VERSION 5.8 ;
BUSBITCHARS "[]" ;
DIVIDERCHAR "/" ;
UNITS
    DATABASE MICRONS 1000 ;
END UNITS

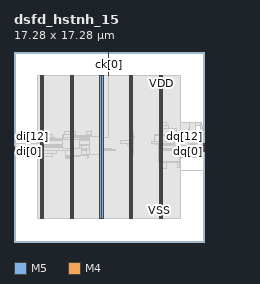
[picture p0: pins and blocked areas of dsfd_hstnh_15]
MACRO dsfd_hstnh_15
  FOREIGN dsfd_hstnh_15 0 0 ;
  CLASS BLOCK ;
  SIZE 17.28 BY 17.28 ;
  PIN ck[0]
    DIRECTION INPUT ;
    USE SIGNAL ;
    PORT
      LAYER M5 ;
        RECT  8.592 17.196 8.616 17.28 ;
    END
    PORT
      LAYER M5 ;
        RECT  8.592 15.143 8.616 17.232 ;
    END
  END ck[0]
  PIN di[0]
    DIRECTION INPUT ;
    USE SIGNAL ;
    PORT
      LAYER M4 ;
        RECT  0 8.256 0.084 8.28 ;
    END
  END di[0]
  PIN di[10]
    DIRECTION INPUT ;
    USE SIGNAL ;
    PORT
      LAYER M4 ;
        RECT  0 8.736 0.084 8.76 ;
    END
  END di[10]
  PIN di[11]
    DIRECTION INPUT ;
    USE SIGNAL ;
    PORT
      LAYER M4 ;
        RECT  0 8.784 0.084 8.808 ;
    END
  END di[11]
  PIN di[12]
    DIRECTION INPUT ;
    USE SIGNAL ;
    PORT
      LAYER M4 ;
        RECT  0 8.832 0.084 8.856 ;
    END
  END di[12]
  PIN di[13]
    DIRECTION INPUT ;
    USE SIGNAL ;
    PORT
      LAYER M4 ;
        RECT  0 8.88 0.084 8.904 ;
    END
  END di[13]
  PIN di[14]
    DIRECTION INPUT ;
    USE SIGNAL ;
    PORT
      LAYER M4 ;
        RECT  0 8.928 0.084 8.952 ;
    END
  END di[14]
  PIN di[1]
    DIRECTION INPUT ;
    USE SIGNAL ;
    PORT
      LAYER M4 ;
        RECT  0 8.304 0.084 8.328 ;
    END
  END di[1]
  PIN di[2]
    DIRECTION INPUT ;
    USE SIGNAL ;
    PORT
      LAYER M4 ;
        RECT  0 8.352 0.084 8.376 ;
    END
  END di[2]
  PIN di[3]
    DIRECTION INPUT ;
    USE SIGNAL ;
    PORT
      LAYER M4 ;
        RECT  0 8.4 0.084 8.424 ;
    END
  END di[3]
  PIN di[4]
    DIRECTION INPUT ;
    USE SIGNAL ;
    PORT
      LAYER M4 ;
        RECT  0 8.448 0.084 8.472 ;
    END
  END di[4]
  PIN di[5]
    DIRECTION INPUT ;
    USE SIGNAL ;
    PORT
      LAYER M4 ;
        RECT  0 8.496 0.084 8.52 ;
    END
  END di[5]
  PIN di[6]
    DIRECTION INPUT ;
    USE SIGNAL ;
    PORT
      LAYER M4 ;
        RECT  0 8.544 0.084 8.568 ;
    END
  END di[6]
  PIN di[7]
    DIRECTION INPUT ;
    USE SIGNAL ;
    PORT
      LAYER M4 ;
        RECT  0 8.592 0.084 8.616 ;
    END
  END di[7]
  PIN di[8]
    DIRECTION INPUT ;
    USE SIGNAL ;
    PORT
      LAYER M4 ;
        RECT  0 8.64 0.084 8.664 ;
    END
  END di[8]
  PIN di[9]
    DIRECTION INPUT ;
    USE SIGNAL ;
    PORT
      LAYER M4 ;
        RECT  0 8.688 0.084 8.712 ;
    END
  END di[9]
  PIN dq[0]
    DIRECTION OUTPUT ;
    USE SIGNAL ;
    PORT
      LAYER M4 ;
        RECT  17.196 8.256 17.28 8.28 ;
    END
  END dq[0]
  PIN dq[10]
    DIRECTION OUTPUT ;
    USE SIGNAL ;
    PORT
      LAYER M4 ;
        RECT  17.196 8.736 17.28 8.76 ;
    END
  END dq[10]
  PIN dq[11]
    DIRECTION OUTPUT ;
    USE SIGNAL ;
    PORT
      LAYER M4 ;
        RECT  17.196 8.784 17.28 8.808 ;
    END
  END dq[11]
  PIN dq[12]
    DIRECTION OUTPUT ;
    USE SIGNAL ;
    PORT
      LAYER M4 ;
        RECT  17.196 8.832 17.28 8.856 ;
    END
  END dq[12]
  PIN dq[13]
    DIRECTION OUTPUT ;
    USE SIGNAL ;
    PORT
      LAYER M4 ;
        RECT  17.196 8.88 17.28 8.904 ;
    END
  END dq[13]
  PIN dq[14]
    DIRECTION OUTPUT ;
    USE SIGNAL ;
    PORT
      LAYER M4 ;
        RECT  17.196 8.928 17.28 8.952 ;
    END
  END dq[14]
  PIN dq[1]
    DIRECTION OUTPUT ;
    USE SIGNAL ;
    PORT
      LAYER M4 ;
        RECT  17.196 8.304 17.28 8.328 ;
    END
  END dq[1]
  PIN dq[2]
    DIRECTION OUTPUT ;
    USE SIGNAL ;
    PORT
      LAYER M4 ;
        RECT  17.196 8.352 17.28 8.376 ;
    END
  END dq[2]
  PIN dq[3]
    DIRECTION OUTPUT ;
    USE SIGNAL ;
    PORT
      LAYER M4 ;
        RECT  17.196 8.4 17.28 8.424 ;
    END
  END dq[3]
  PIN dq[4]
    DIRECTION OUTPUT ;
    USE SIGNAL ;
    PORT
      LAYER M4 ;
        RECT  17.196 8.448 17.28 8.472 ;
    END
  END dq[4]
  PIN dq[5]
    DIRECTION OUTPUT ;
    USE SIGNAL ;
    PORT
      LAYER M4 ;
        RECT  17.196 8.496 17.28 8.52 ;
    END
  END dq[5]
  PIN dq[6]
    DIRECTION OUTPUT ;
    USE SIGNAL ;
    PORT
      LAYER M4 ;
        RECT  17.196 8.544 17.28 8.568 ;
    END
  END dq[6]
  PIN dq[7]
    DIRECTION OUTPUT ;
    USE SIGNAL ;
    PORT
      LAYER M4 ;
        RECT  17.196 8.592 17.28 8.616 ;
    END
  END dq[7]
  PIN dq[8]
    DIRECTION OUTPUT ;
    USE SIGNAL ;
    PORT
      LAYER M4 ;
        RECT  17.196 8.64 17.28 8.664 ;
    END
  END dq[8]
  PIN dq[9]
    DIRECTION OUTPUT ;
    USE SIGNAL ;
    PORT
      LAYER M4 ;
        RECT  17.196 8.688 17.28 8.712 ;
    END
  END dq[9]
  PIN VDD
    DIRECTION INOUT ;
    USE POWER ;
    PORT
      LAYER M5 ;
        RECT  13.392 2.151 13.512 15.129 ;
        RECT  10.692 2.151 10.812 15.129 ;
        RECT  7.992 2.151 8.112 15.129 ;
        RECT  5.292 2.151 5.412 15.129 ;
        RECT  2.592 2.151 2.712 15.129 ;
    END
  END VDD
  PIN VSS
    DIRECTION INOUT ;
    USE GROUND ;
    PORT
      LAYER M5 ;
        RECT  13.2 2.137 13.32 15.143 ;
        RECT  10.5 2.137 10.62 15.143 ;
        RECT  7.8 2.137 7.92 15.143 ;
        RECT  5.1 2.137 5.22 15.143 ;
        RECT  2.4 2.137 2.52 15.143 ;
    END
  END VSS
  # OT_OBS_CLOSED layer=M5 d_um=1.536 added=0
  OBS
    LAYER RVTN ;
     RECT  2.16 2.16 15.12 2.295 ;
     RECT  2.16 2.565 15.12 2.835 ;
     RECT  2.16 3.105 15.12 3.375 ;
     RECT  2.16 3.645 15.12 3.915 ;
     RECT  2.16 4.185 15.12 4.455 ;
     RECT  2.16 4.725 15.12 4.995 ;
     RECT  2.16 5.265 15.12 5.535 ;
     RECT  2.16 5.805 15.12 6.075 ;
     RECT  2.16 6.345 15.12 6.615 ;
     RECT  2.16 6.885 15.12 7.155 ;
     RECT  2.16 7.425 15.12 7.695 ;
     RECT  2.16 7.965 15.12 8.235 ;
     RECT  2.16 8.505 15.12 8.775 ;
     RECT  2.16 9.045 15.12 9.315 ;
     RECT  2.16 9.585 15.12 9.855 ;
     RECT  2.16 10.125 15.12 10.395 ;
     RECT  2.16 10.665 15.12 10.935 ;
     RECT  2.16 11.205 15.12 11.475 ;
     RECT  2.16 11.745 15.12 12.015 ;
     RECT  2.16 12.285 15.12 12.555 ;
     RECT  2.16 12.825 15.12 13.095 ;
     RECT  2.16 13.365 15.12 13.635 ;
     RECT  2.16 13.905 15.12 14.175 ;
     RECT  2.16 14.445 15.12 14.715 ;
     RECT  2.16 14.985 15.12 15.12 ;
    LAYER RVTP ;
     RECT  2.16 2.295 15.12 2.565 ;
     RECT  2.16 2.835 15.12 3.105 ;
     RECT  2.16 3.375 15.12 3.645 ;
     RECT  2.16 3.915 15.12 4.185 ;
     RECT  2.16 4.455 15.12 4.725 ;
     RECT  2.16 4.995 15.12 5.265 ;
     RECT  2.16 5.535 15.12 5.805 ;
     RECT  2.16 6.075 15.12 6.345 ;
     RECT  2.16 6.615 15.12 6.885 ;
     RECT  2.16 7.155 15.12 7.425 ;
     RECT  2.16 7.695 15.12 7.965 ;
     RECT  2.16 8.235 15.12 8.505 ;
     RECT  2.16 8.775 15.12 9.045 ;
     RECT  2.16 9.315 15.12 9.585 ;
     RECT  2.16 9.855 15.12 10.125 ;
     RECT  2.16 10.395 15.12 10.665 ;
     RECT  2.16 10.935 15.12 11.205 ;
     RECT  2.16 11.475 15.12 11.745 ;
     RECT  2.16 12.015 15.12 12.285 ;
     RECT  2.16 12.555 15.12 12.825 ;
     RECT  2.16 13.095 15.12 13.365 ;
     RECT  2.16 13.635 15.12 13.905 ;
     RECT  2.16 14.175 15.12 14.445 ;
     RECT  2.16 14.715 15.12 14.985 ;
    LAYER M1 ;
     RECT  2.16 2.151 15.12 15.129 ;
    LAYER M2 ;
     RECT  0.139 7.902 0.535 8.496 ;
     RECT  0.535 7.74 2.16 8.496 ;
     RECT  2.16 2.151 15.12 15.129 ;
     RECT  15.12 7.704 15.935 10.854 ;
     RECT  15.935 7.704 15.971 8.874 ;
     RECT  15.971 7.704 16.007 8.532 ;
     RECT  15.935 9.864 16.511 10.854 ;
     RECT  16.511 10.566 17.015 10.854 ;
     RECT  16.007 7.704 17.087 7.722 ;
     RECT  17.015 10.566 17.123 10.584 ;
     RECT  15.12 6.516 17.267 6.534 ;
    LAYER M3 ;
     RECT  2.415 2.143 2.505 2.413 ;
     RECT  5.115 2.143 5.205 2.413 ;
     RECT  7.815 2.143 7.905 2.413 ;
     RECT  10.515 2.143 10.605 2.413 ;
     RECT  13.215 2.143 13.305 2.413 ;
     RECT  13.215 2.413 13.497 6.655 ;
     RECT  13.215 6.655 13.842 7.195 ;
     RECT  14.832 6.817 15.03 7.195 ;
     RECT  13.215 7.195 15.03 7.357 ;
     RECT  5.115 2.413 5.397 7.627 ;
     RECT  4.68 7.627 5.397 7.663 ;
     RECT  6.696 7.627 6.714 7.663 ;
     RECT  17.244 6.511 17.262 7.699 ;
     RECT  4.644 7.663 5.397 7.735 ;
     RECT  2.415 2.413 2.697 7.771 ;
     RECT  7.815 2.413 8.097 7.771 ;
     RECT  4.644 7.735 5.922 7.861 ;
     RECT  6.696 7.663 6.75 7.861 ;
     RECT  7.815 7.771 8.154 7.861 ;
     RECT  4.644 7.861 6.75 7.889 ;
     RECT  0.54 7.735 0.558 7.897 ;
     RECT  6.12 7.889 6.75 7.915 ;
     RECT  7.776 7.861 8.154 7.915 ;
     RECT  10.515 2.413 10.797 7.969 ;
     RECT  2.415 7.771 3.546 8.041 ;
     RECT  17.064 7.699 17.262 8.189 ;
     RECT  2.415 8.041 3.906 8.299 ;
     RECT  2.304 8.299 3.906 8.311 ;
     RECT  4.644 7.889 5.397 8.311 ;
     RECT  6.12 7.915 8.154 8.311 ;
     RECT  13.104 7.357 15.03 8.311 ;
     RECT  15.984 7.771 16.002 8.311 ;
     RECT  6.12 8.311 9.27 8.429 ;
     RECT  13.104 8.311 16.002 8.429 ;
     RECT  6.12 8.429 8.838 8.465 ;
     RECT  0.144 7.897 0.558 8.477 ;
     RECT  13.104 8.429 15.03 8.477 ;
     RECT  6.12 8.465 8.154 8.537 ;
     RECT  17.064 8.189 17.118 8.539 ;
     RECT  0.144 8.477 0.522 8.573 ;
     RECT  2.304 8.311 5.397 8.587 ;
     RECT  0.504 8.573 0.522 8.669 ;
     RECT  2.268 8.587 5.397 8.683 ;
     RECT  2.232 8.683 5.397 8.731 ;
     RECT  6.12 8.537 7.074 8.731 ;
     RECT  10.515 7.969 10.854 8.779 ;
     RECT  13.104 8.477 14.886 8.813 ;
     RECT  2.232 8.731 7.074 8.843 ;
     RECT  13.104 8.813 14.634 8.851 ;
     RECT  15.876 8.429 16.002 8.923 ;
     RECT  16.992 8.539 17.118 8.923 ;
     RECT  12.852 8.851 14.634 8.941 ;
     RECT  7.815 8.537 8.154 8.969 ;
     RECT  10.332 8.779 10.854 8.977 ;
     RECT  12.528 8.941 14.634 9.113 ;
     RECT  9.648 8.977 10.854 9.239 ;
     RECT  2.304 8.843 7.074 9.275 ;
     RECT  10.26 9.239 10.854 9.275 ;
     RECT  2.34 9.275 7.074 9.311 ;
     RECT  4.428 9.311 7.074 9.391 ;
     RECT  7.815 8.969 8.097 9.391 ;
     RECT  2.34 9.311 3.654 9.509 ;
     RECT  10.515 9.275 10.854 9.517 ;
     RECT  2.34 9.509 3.474 9.545 ;
     RECT  4.428 9.391 8.097 9.545 ;
     RECT  10.515 9.517 10.926 9.617 ;
     RECT  4.464 9.545 7.074 9.653 ;
     RECT  12.816 9.113 14.634 9.661 ;
     RECT  2.376 9.545 3.474 9.779 ;
     RECT  2.376 9.779 3.006 9.815 ;
     RECT  4.464 9.653 5.562 9.815 ;
     RECT  6.588 9.653 7.074 9.815 ;
     RECT  12.816 9.661 14.778 9.815 ;
     RECT  2.415 9.815 3.006 9.887 ;
     RECT  15.876 8.923 17.118 9.887 ;
     RECT  10.515 9.617 10.854 9.923 ;
     RECT  4.608 9.815 5.562 10.049 ;
     RECT  6.624 9.815 7.074 10.049 ;
     RECT  5.115 10.049 5.454 10.085 ;
     RECT  7.056 10.049 7.074 10.157 ;
     RECT  15.876 9.887 15.894 10.319 ;
     RECT  13.215 9.815 14.778 10.355 ;
     RECT  16.992 9.887 17.118 10.589 ;
     RECT  13.215 10.355 14.094 10.625 ;
     RECT  16.992 10.589 17.01 10.859 ;
     RECT  13.215 10.625 13.878 10.895 ;
     RECT  2.415 9.887 2.697 14.867 ;
     RECT  5.115 10.085 5.397 14.867 ;
     RECT  7.815 9.545 8.097 14.867 ;
     RECT  10.515 9.923 10.797 14.867 ;
     RECT  13.215 10.895 13.497 14.867 ;
     RECT  2.415 14.867 2.505 15.137 ;
     RECT  5.115 14.867 5.205 15.137 ;
     RECT  7.815 14.867 7.905 15.137 ;
     RECT  10.515 14.867 10.605 15.137 ;
     RECT  13.215 14.867 13.305 15.137 ;
    LAYER M4 ;
     RECT  0.06 8.256 0.173 8.952 ;
     RECT  0.173 8.304 2.404 8.952 ;
     RECT  2.404 8.304 2.408 9 ;
     RECT  2.408 2.148 2.512 15.132 ;
     RECT  2.512 2.418 2.704 14.862 ;
     RECT  2.704 8.784 2.801 9.384 ;
     RECT  2.801 9.36 4.381 9.384 ;
     RECT  4.381 8.496 4.412 9.384 ;
     RECT  4.412 8.496 5.108 9.768 ;
     RECT  5.108 2.148 5.212 15.132 ;
     RECT  5.212 2.418 5.404 14.862 ;
     RECT  5.404 8.496 5.939 9.576 ;
     RECT  5.939 8.496 6.577 8.52 ;
     RECT  6.577 7.92 6.901 8.52 ;
     RECT  5.939 9.552 6.901 9.576 ;
     RECT  6.901 7.92 7.808 9.576 ;
     RECT  7.808 2.148 7.912 15.132 ;
     RECT  7.912 2.418 8.104 14.862 ;
     RECT  8.104 9.552 8.627 9.576 ;
     RECT  10.508 2.148 10.612 15.132 ;
     RECT  10.612 2.418 10.804 14.862 ;
     RECT  13.208 2.148 13.312 15.132 ;
     RECT  13.312 2.418 13.504 14.862 ;
     RECT  14.821 8.64 14.857 8.664 ;
     RECT  14.857 8.64 14.965 8.808 ;
     RECT  14.965 8.256 15.865 8.808 ;
     RECT  15.865 8.256 16.477 8.904 ;
     RECT  16.477 8.256 17.089 8.952 ;
     RECT  17.089 8.16 17.244 8.952 ;
     RECT  17.244 8.16 17.273 8.184 ;
    LAYER M5 ;
     RECT  2.4 2.137 2.52 2.151 ;
     RECT  5.1 2.137 5.22 2.151 ;
     RECT  7.8 2.137 7.92 2.151 ;
     RECT  10.5 2.137 10.62 2.151 ;
     RECT  13.2 2.137 13.32 2.151 ;
     RECT  5.1 2.151 5.412 8.485 ;
     RECT  5.1 8.485 5.928 9.349 ;
     RECT  4.464 9.349 5.928 9.491 ;
     RECT  7.8 2.151 8.112 9.541 ;
     RECT  4.464 9.491 5.412 9.779 ;
     RECT  2.4 2.151 2.712 15.129 ;
     RECT  5.1 9.779 5.412 15.129 ;
     RECT  10.5 2.151 10.812 15.129 ;
     RECT  13.2 2.151 13.512 15.129 ;
     RECT  2.4 15.129 2.52 15.143 ;
     RECT  5.1 15.129 5.22 15.143 ;
     RECT  7.8 9.541 8.616 15.143 ;
     RECT  10.5 15.129 10.62 15.143 ;
     RECT  13.2 15.129 13.32 15.143 ;
  END
END dsfd_hstnh_15
END LIBRARY
